! (c) 2009  Infineon Technologies AG, Munich
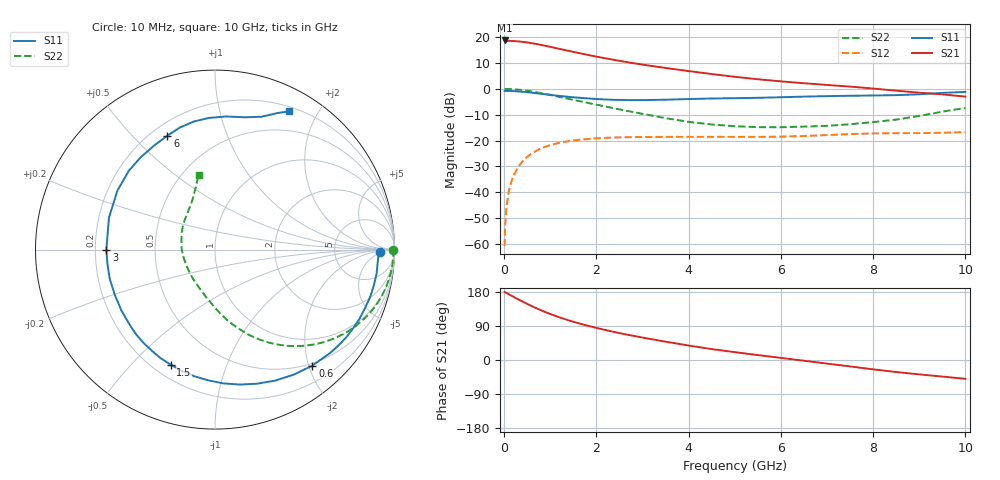
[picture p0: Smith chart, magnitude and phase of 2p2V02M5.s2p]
! Infineon Technologies  Discrete & RF Semiconductors
! BFP420
! VCE =  2.0 V,  IC =  2.5 mA
! Common Emitter S-Parameters:  Nov 2009
# GHz  S  MA  R  50
!  f  S11  S21  S12  S22
! GHz  MAG  ANG  MAG  ANG  MAG  ANG  MAG  ANG
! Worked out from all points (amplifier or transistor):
!   46 points, 10 MHz to 10 GHz, reference 50 ohm
!   highest |S21| = 18.7 dB at 10 MHz (marker M1)
!   |S21| within 3 dB of that: start of sweep to 1.134 GHz
!   unconditionally stable (mu >= 1): 3.71 GHz to end of sweep
!   at 300 MHz: K = 0.05, MSG = 24.4 dB, |S12| = -30.4 dB
!   at 1.7 GHz: K = 0.40, MSG = 16.6 dB, |S12| = -19.6 dB
!   at 10 GHz: K = 1.19, MAG = 4.2 dB, |S12| = -16.8 dB
!   lowest NFmin = 0.55 dB at 900 MHz
!   S11 on the Smith chart (normalised r, x): 10 MHz: 23, -5; 600 MHz: 0.46, -2.06; 1.5 GHz: 0.27, -0.65; 3 GHz: 0.25, -0.00; 6 GHz: 0.26, +0.63; 10 GHz: 0.25, +1.64
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0.01  0.9192 -1.0  8.655 179.2  0.0009 126.1  0.9921 0.0
0.02  0.9109 -1.7  8.427 179.0  0.0021 91.2  0.9938 -0.9
0.05  0.9095 -4.2  8.464 176.7  0.0052 88.7  0.9939 -2.5
0.15  0.907 -12.7  8.484 170.2  0.0153 82.9  0.9878 -7.5
0.35  0.8855 -29.7  8.235 157.3  0.0349 73.4  0.957 -17.3
0.5  0.8622 -41.9  7.913 148.0  0.0481 66.6  0.9199 -24.3
0.6  0.8439 -50.0  7.663 142.1  0.0562 62.2  0.8914 -28.7
0.8  0.8032 -65.3  7.087 131.2  0.0701 54.3  0.8278 -36.8
1  0.7645 -79.6  6.51 121.4  0.0814 47.3  0.7619 -44.0
1.2  0.7295 -93.0  5.948 112.5  0.0902 41.2  0.6982 -50.4
1.5  0.6866 -111.1  5.202 101.0  0.1001 33.5  0.6121 -58.6
1.7  0.6637 -122.3  4.777 94.0  0.1048 29.0  0.5613 -63.4
2.2  0.6224 -146.8  3.9 79.0  0.1125 20.0  0.4549 -73.9
2.6  0.6086 -164.6  3.37 68.5  0.1156 14.1  0.385 -81.8
3  0.6053 -180.0  2.949 59.2  0.1169 9.5  0.3282 -89.3
3.5  0.617 163.2  2.536 48.3  0.1174 4.8  0.2709 -100.2
4.5  0.6509 137.5  1.936 28.8  0.1176 -1.6  0.2043 -126.5
5.5  0.6712 120.5  1.535 13.0  0.1175 -5.3  0.1815 -153.3
6  0.6881 112.7  1.398 5.6  0.1188 -6.2  0.1808 -167.7
7  0.7233 99.4  1.191 -9.5  0.1272 -8.9  0.1921 166.5
8.5  0.7556 77.3  0.921 -31.7  0.1384 -18.2  0.2538 127.4
10  0.8739 61.8  0.707 -49.7  0.1451 -24.0  0.4267 102.4
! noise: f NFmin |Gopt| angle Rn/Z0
0.9  0.55  0.41  33  0.2
1.8  1.02  0.24  78  0.16
2.4  1.11  0.26  103  0.15
3  1.28  0.27  140  0.11
4  1.5  0.34  -163  0.1
5  1.85  0.4  -130  0.26
6  2.56  0.5  -109  0.35
